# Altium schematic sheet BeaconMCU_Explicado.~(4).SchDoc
size A4

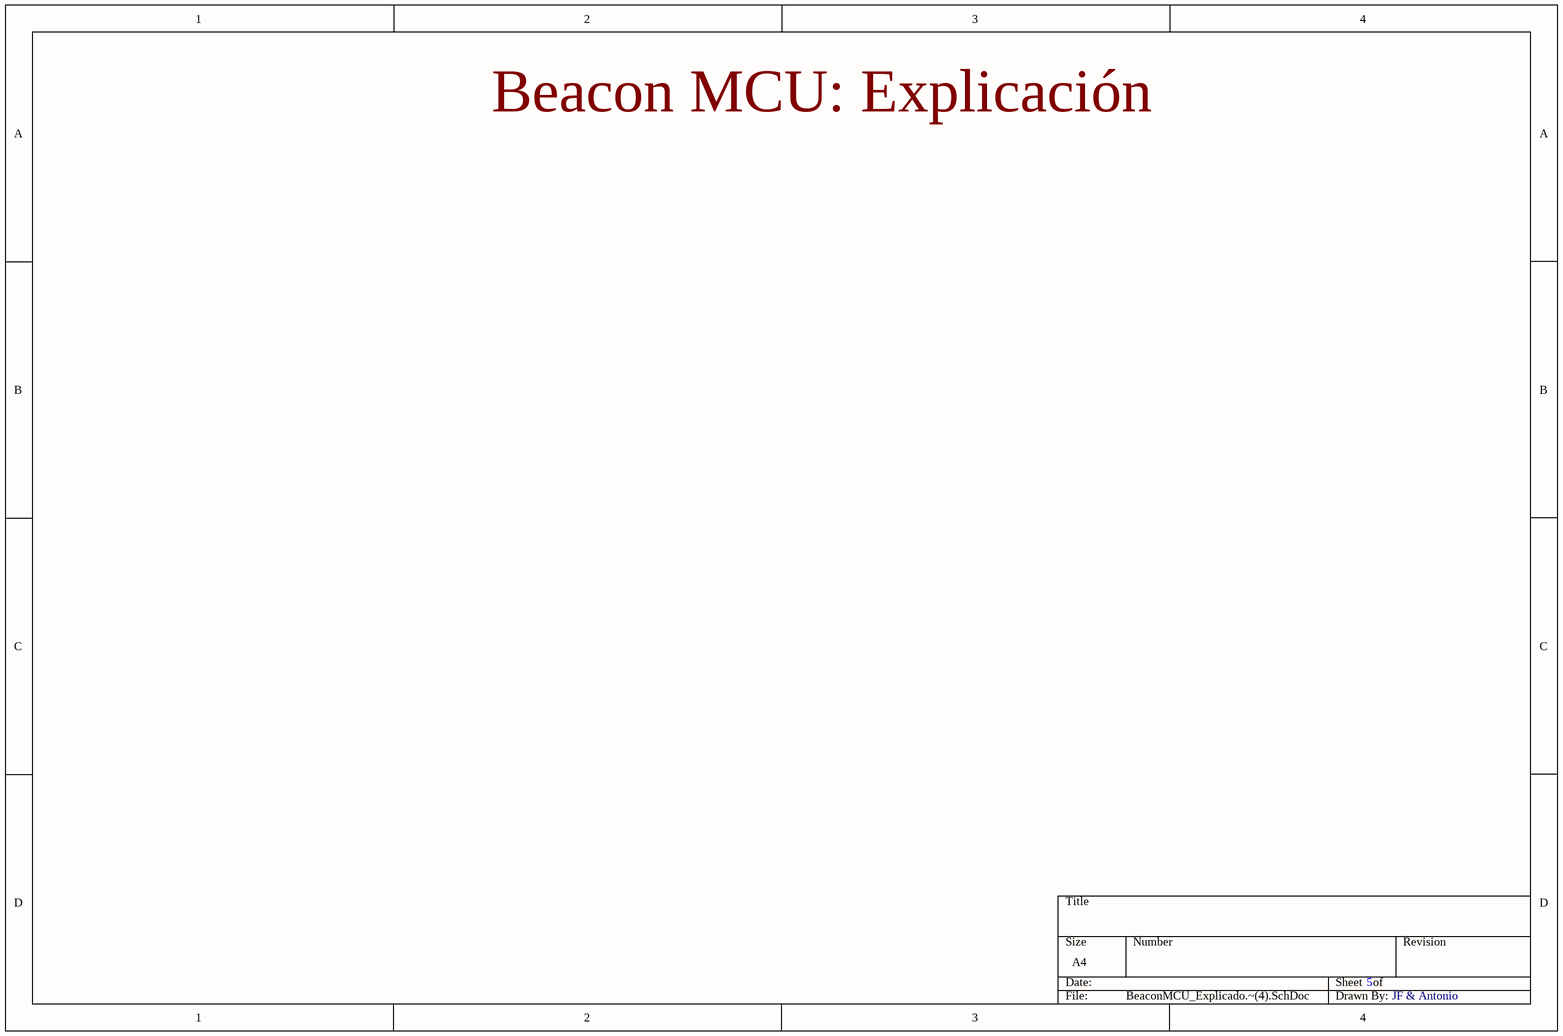
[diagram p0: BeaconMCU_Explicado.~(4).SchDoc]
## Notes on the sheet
- Beacon MCU: Explicación
- 5
- JF & Antonio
